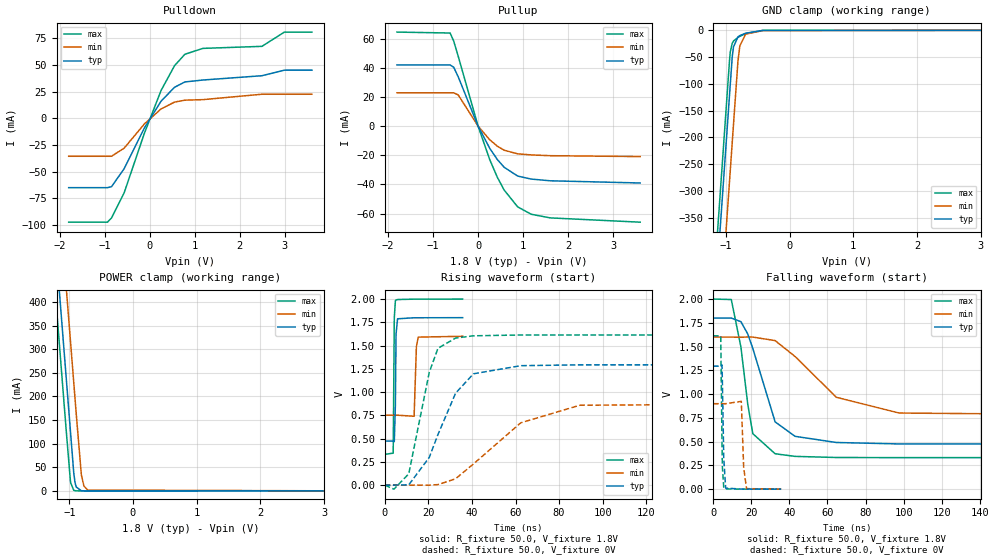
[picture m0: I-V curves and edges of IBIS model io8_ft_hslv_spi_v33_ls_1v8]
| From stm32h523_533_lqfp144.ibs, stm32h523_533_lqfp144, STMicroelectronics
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[Model]   io8_ft_hslv_spi_v33_ls_1v8
Model_type I/O
Polarity   Non-Inverting
Enable   Active-Low
| CAP_THRESHOLD on pad IOFT is "UDTCAPC" :
| Rising=20.0% of vddiom   Falling=80.0% of vddiom
| C_comp min and max val. don't necessarily correlate with the min and max pvt
| but are the smallest and greatest pad capacitance found.
| var   typ   min   max
C_comp   3.69213pF  3.66975pF  3.86726pF
|C_comp_pullup   2.29915pF  2.22620pF  2.22545pF
|C_comp_pulldown   1.39298pF  1.44355pF  1.64181pF
Vinl = 480.0mV
Vinh = 1.4V
Vmeas = 900.0mV   | Reference voltage for timing measurements
Cref  = 50.0pF   | Timing specification test load capacitance value
Rref  = 100.0MOhm   | Timing specification test load resistance value
Vref  = 900.0mV   | Timing specification test load voltage
[Model Spec]
| TIME_THRESHOLD on pin ZIV33M is "CMOS" :
| Rising=40.0% of vddiom   Falling=60.0% of vddiom
Vinl 693.80000mV 621.80000mV 774.80000mV
Vinh 1.05820V 933.20000mV 1.16320V
| variable   typ   min   max
[Temperature Range] 25.0 125.0 -40.0
| variable   typ   min   max
[Voltage Range] 1.8V 1.6V 2.0V
| variable   typ   min   max
[POWER Clamp Reference] 1.8V 1.6V 2.0V
| variable   typ   min   max
[GND Clamp Reference] 0V 0V 0V
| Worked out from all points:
|   slope of the pulldown table from 0 to 0.27 V, typ, clamps not added: 15.8 ohm
|   slope of the pullup table from 0 to 0.27 V, typ, clamps not added: 17.1 ohm
|   GND clamp passes 1 mA (typ) near -0.52 V on its own axis
|   POWER clamp passes 1 mA (typ) near -0.84 V on its own axis
|   rising waveform, R_fixture 50.0, V_fixture 1.8V: 20-80 % time 282ps typ, 447ps min, 240ps max; typ from 0.474 V to 1.8 V
|   falling waveform, R_fixture 50.0, V_fixture 1.8V: 20-80 % time 11.9ns typ, 28.6ns min, 7.28ns max; typ from 1.8 V to 0.474 V
|   rising waveform, R_fixture 50.0, V_fixture 0V: 20-80 % time 14.5ns typ, 28.2ns min, 8.37ns max; typ from 0 V to 1.29 V
|   falling waveform, R_fixture 50.0, V_fixture 0V: 20-80 % time 737ps typ, 1.07ns min, 544ps max; typ from 1.29 V to 0 V
[POWER Clamp]
-1.8V     1.518A     1.709A     1.407A
-1.23V    548.8mA    740.2mA    437.5mA
-1.16V    429.8mA    621.2mA    318.5mA
-1.05V    242.8mA    434.2mA    131.5mA
-980mV    123.8mA    315.2mA    17.95mA
-930mV    38.81mA    230.2mA    1.49mA
-910mV    17.82mA    196.2mA    550.8uA
-890mV    8.18mA     162.2mA    203.5uA
-810mV    363.5uA    33.6mA     3.797uA
-770mV    76.62uA    10.47mA    518.8nA
-710mV    7.416uA    1.822mA    26.33nA
3.6V      0A         0A         0A
[GND Clamp]
-1.8V     -1.579A    -1.74A     -1.515A
-1.24V    -627.3mA   -788.3mA   -562.7mA
-1.05V    -304.3mA   -465.3mA   -239.7mA
-940mV    -117.3mA   -278.3mA   -52.69mA
-930mV    -100.3mA   -261.3mA   -40.52mA
-900mV    -50.11mA   -210.3mA   -24.23mA
-880mV    -30.95mA   -176.3mA   -20.02mA
-810mV    -12.18mA   -57.97mA   -13.23mA
-780mV    -9.807mA   -29.1mA    -11.19mA
-690mV    -5.41mA    -7.142mA   -6.184mA
-420mV    -170.4uA   -446.1uA   -81.94uA
3.6V      5.755nA    953.2nA    228.2pA
| variable   typ   min   max
[Pullup Reference] 1.8V 1.6V 2.0V
| variable   typ   min   max
[Pulldown Reference] 0V 0V 0V
[Pullup]
-1.8V     41.86mA    22.78mA    64.4mA
-620mV    41.86mA    22.78mA    63.76mA
-540mV    40.31mA    22.78mA    58.19mA
-440mV    33.74mA    21.31mA    47.82mA
0V        7.5pA      698pA      4.403pA
260mV     -15.28mA   -9.412mA   -23.06mA
430mV     -23.01mA   -13.84mA   -35.21mA
580mV     -28.25mA   -16.58mA   -43.88mA
880mV     -34.28mA   -19.05mA   -55.41mA
1.18V     -36.34mA   -19.79mA   -60.45mA
1.6V      -37.52mA   -20.32mA   -62.94mA
3.6V      -39.03mA   -20.93mA   -65.9mA
[Pulldown]
-1.8V     -65.02mA   -35.56mA   -97.42mA
-940mV    -65.02mA   -35.56mA   -97.42mA
-850mV    -64.17mA   -35.56mA   -93.49mA
-570mV    -47.32mA   -28.01mA   -70.04mA
-120mV    -9.088mA   -5.279mA   -14.07mA
250mV     16.04mA    8.832mA    26.05mA
550mV     29.17mA    15.25mA    49.41mA
780mV     34.17mA    17.07mA    60.14mA
1.18V     35.97mA    17.56mA    65.65mA
2.49V     40mA       22.62mA    67.56mA
2.99V     45.21mA    22.62mA    80.94mA
3.6V      45.21mA    22.62mA    80.94mA
[Ramp]
dV/dt_r 776.15304mV/13.93065ns 539.47968mV/27.77354ns 968.5432mV/7.93366ns
dV/dt_f 795.7871mV/11.67213ns 508.95919mV/28.10707ns 1.00099V/6.47052ns
R_load = 50.0
| Removed startup time: 0s 0s 0s  .
| Removed end time: 35.75ns.
[Rising Waveform]
R_fixture   = 50.0
V_fixture   = 1.8V
V_fixture_min = 1.6V
V_fixture_max = 2.0V
0s        473.7mV    751.7mV    331.7mV
3.85ns    473.7mV    751.7mV    343.5mV
4.35ns    467.7mV    751.7mV    1.796V
4.85ns    856.5mV    751.7mV    1.982V
5.15ns    1.621V     751.7mV    1.99V
5.85ns    1.788V     751.7mV    1.995V
13.45ns   1.799V     740.6mV    1.999V
14.5ns    1.799V     1.489V     1.999V
15.35ns   1.799V     1.591V     1.999V
35.75ns   1.8V       1.6V       2V
| Removed startup time: 0s 0s 0s  .
| Removed end time: 398.75ns.
[Falling Waveform]
R_fixture   = 50.0
V_fixture   = 1.8V
V_fixture_min = 1.6V
V_fixture_max = 2.0V
0s        1.8V       1.6V       2V
9.55ns    1.8V       1.6V       1.995V
14.6ns    1.762V     1.598V     1.495V
18.2ns    1.632V     1.601V     892.6mV
20.85ns   1.48V      1.6V       583.5mV
32.55ns   708.2mV    1.563V     372.7mV
43ns      555.9mV    1.396V     344.9mV
64.7ns    491.1mV    966.6mV    333.3mV
97.65ns   475.9mV    801mV      331.8mV
398.8ns   473.7mV    751.7mV    331.7mV
| Removed startup time: 0s 0s 0s  .
| Removed end time: 398.6ns.
[Rising Waveform]
R_fixture   = 50.0
V_fixture   = 0V
V_fixture_min = 0V
V_fixture_max = 0V
0s        158.1nV    435.5nV    115.8nV
4.2ns     894.4uV    441.7nV    -43.1mV
11ns      3.201mV    -184.1nV   122.3mV
20.4ns    298.4mV    3.223uV    1.212V
24.4ns    544.4mV    5.946mV    1.471V
32.5ns    989.1mV    68.92mV    1.581V
40.7ns    1.197V     228.3mV    1.605V
62.4ns    1.284V     670.1mV    1.614V
89.5ns    1.293V     858.9mV    1.614V
398.6ns   1.294V     899.1mV    1.614V
| Removed startup time: 0s 0s 0s  .
| Removed end time: 35.75ns.
[Falling Waveform]
R_fixture   = 50.0
V_fixture   = 0V
V_fixture_min = 0V
V_fixture_max = 0V
0s        1.294V     899.2mV    1.614V
4ns       1.294V     899.2mV    1.612V
4.65ns    1.308V     899.2mV    534.1mV
4.85ns    1.159V     899.2mV    240.6mV
5.6ns     322.4mV    899.2mV    13.79mV
6.6ns     11.29mV    899.2mV    3.064mV
14.8ns    1.235mV    923.6mV    717uV
16.05ns   1.083mV    228mV      551.4uV
17.55ns   861.2uV    5.66mV     427.1uV
35.75ns   149uV      591.9uV    79.89uV
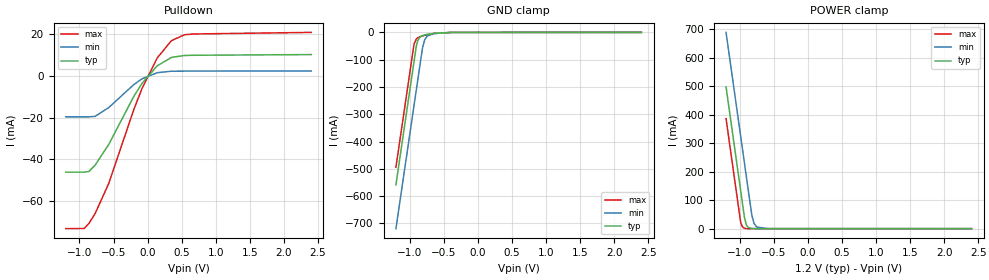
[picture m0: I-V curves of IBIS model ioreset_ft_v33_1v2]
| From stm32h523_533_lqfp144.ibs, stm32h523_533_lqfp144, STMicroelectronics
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[Model]   ioreset_ft_v33_1v2
Model_type I/O_open_drain
Polarity   Inverting
Enable   Active-Low
| CAP_THRESHOLD on pad IOFT is "UDTCAPC" :
| Rising=20.0% of vddiom   Falling=80.0% of vddiom
| C_comp min and max val. don't necessarily correlate with the min and max pvt
| but are the smallest and greatest pad capacitance found.
| var   typ   min   max
C_comp   2.84130pF  2.76215pF  2.88040pF
|C_comp_pulldown   2.84130pF  2.76215pF  2.88040pF
Vinl = 450.0mV
Vinh = 660.0mV
Vmeas = 600.0mV   | Reference voltage for timing measurements
Cref  = 50.0pF   | Timing specification test load capacitance value
Rref  = 1.0MOhm   | Timing specification test load resistance value
Vref  = 660.0mV   | Timing specification test load voltage
[Model Spec]
| TIME_THRESHOLD on pin ZIV33M is "CMOS" :
| Rising=40.0% of vddiom   Falling=60.0% of vddiom
Vinl 443.80000mV 340.80000mV 485.80000mV
Vinh 727.20000mV 529.20000mV 807.20000mV
| variable   typ   min   max
[Temperature Range] 25.0 125.0 -40.0
| variable   typ   min   max
[Voltage Range] 1.2V 900.0mV 1.32V
| variable   typ   min   max
[POWER Clamp Reference] 1.2V 900.0mV 1.32V
| variable   typ   min   max
[GND Clamp Reference] 0V 0V 0V
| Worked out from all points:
|   slope of the pulldown table from 0 to 0.18 V, typ, clamps not added: 30.6 ohm
|   GND clamp passes 1 mA (typ) near -0.52 V on its own axis
|   POWER clamp passes 1 mA (typ) near -0.84 V on its own axis
[POWER Clamp]
-1.2V     497.8mA    689.2mA    386.5mA
-990mV    140.8mA    332.2mA    29.53mA
-980mV    123.8mA    315.2mA    17.95mA
-960mV    89.81mA    281.2mA    6.634mA
-930mV    38.81mA    230.2mA    1.49mA
-900mV    12.07mA    179.2mA    334.8uA
-870mV    3.756mA    128.2mA    75.22uA
-820mV    536.4uA    44.98mA    6.245uA
-790mV    166.9uA    18.76mA    1.403uA
-750mV    35.18uA    5.847mA    191.7nA
-590mV    69.59nA    55.16uA    84.18pA
2.4V      0A         0A         0A
[GND Clamp]
-1.2V     -558.2mA   -719mA     -494.1mA
-940mV    -116.2mA   -277mA     -52.06mA
-930mV    -99.18mA   -260mA     -39.94mA
-900mV    -49.1mA    -209mA     -23.75mA
-880mV    -30.13mA   -175mA     -19.59mA
-850mV    -17.82mA   -124mA     -16.09mA
-810mV    -11.73mA   -56.78mA   -12.9mA
-780mV    -9.44mA    -28.21mA   -10.91mA
-740mV    -7.285mA   -13.16mA   -8.565mA
-640mV    -3.567mA   -4.168mA   -3.948mA
-390mV    -79.81uA   -270.3uA   -28.73uA
2.4V      233.9pA    35.97nA    60.57pA
| variable   typ   min   max
[Pullup Reference] 1.2V 900.0mV 1.32V
| variable   typ   min   max
[Pulldown Reference] 0V 0V 0V
[Pulldown]
-1.2V     -46.17mA   -19.62mA   -73.27mA
-930mV    -46.17mA   -19.62mA   -73.18mA
-860mV    -45.79mA   -19.62mA   -70.72mA
-770mV    -42.8mA    -19.41mA   -66.04mA
-570mV    -32.88mA   -15.18mA   -51.58mA
-200mV    -9.658mA   -4.083mA   -15.89mA
-80mV     -3.488mA   -1.363mA   -5.887mA
140mV     4.817mA    1.546mA    8.585mA
350mV     8.893mA    2.257mA    16.93mA
540mV     9.805mA    2.305mA    19.74mA
670mV     9.907mA    2.32mA     20.12mA
2.4V      10.24mA    2.38mA     20.88mA
[Ramp]
dV/dt_r 297.02691mV/1.29501ns 69.92336mV/4.07755ns 547.69816mV/634.55203ps
dV/dt_f 297.80521mV/59.252ns 69.83691mV/166.01957ns 547.13931mV/28.75647ns
R_load = 50.0
| Removed startup time: 0s 0s 0s  .
| Removed end time: 349.99us.
|[End]
